VERSION 5.7 ;
  NOWIREEXTENSIONATPIN ON ;
  DIVIDERCHAR "/" ;
  BUSBITCHARS "[]" ;
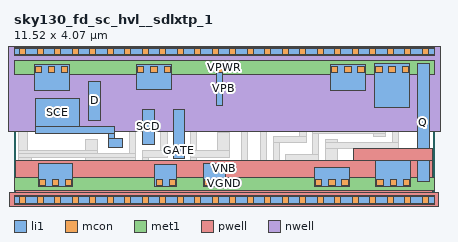
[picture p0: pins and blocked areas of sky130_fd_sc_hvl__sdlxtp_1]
MACRO sky130_fd_sc_hvl__sdlxtp_1
  CLASS BLOCK ;
  FOREIGN sky130_fd_sc_hvl__sdlxtp_1 ;
  ORIGIN 0.000 0.000 ;
  SIZE 11.520 BY 4.070 ;
  PIN D
    ANTENNAGATEAREA 0.585000 ;
    PORT
      LAYER li1 ;
        RECT 2.040 2.185 2.370 3.260 ;
    END
  END D
  PIN GATE
    ANTENNAGATEAREA 0.585000 ;
    PORT
      LAYER li1 ;
        RECT 4.370 1.145 4.665 2.495 ;
    END
  END GATE
  PIN SCD
    ANTENNAGATEAREA 0.585000 ;
    PORT
      LAYER li1 ;
        RECT 3.515 1.525 3.860 2.495 ;
    END
  END SCD
  PIN SCE
    ANTENNAGATEAREA 1.005000 ;
    PORT
      LAYER li1 ;
        RECT 0.585 2.005 1.795 2.775 ;
        RECT 0.585 1.835 2.770 2.005 ;
        RECT 2.600 1.695 2.770 1.835 ;
        RECT 2.600 1.445 2.985 1.695 ;
    END
  END SCE
  PIN VGND
    USE GROUND ;
    PORT
      LAYER li1 ;
        RECT 0.660 0.365 1.610 0.995 ;
        RECT 3.865 0.365 4.455 0.975 ;
        RECT 5.205 0.365 5.795 0.995 ;
        RECT 8.245 0.365 9.195 0.895 ;
        RECT 9.925 0.365 10.875 1.225 ;
      LAYER mcon ;
        RECT 0.690 0.395 0.860 0.565 ;
        RECT 1.050 0.395 1.220 0.565 ;
        RECT 1.410 0.395 1.580 0.565 ;
        RECT 3.895 0.395 4.065 0.565 ;
        RECT 4.255 0.395 4.425 0.565 ;
        RECT 5.235 0.395 5.405 0.565 ;
        RECT 5.595 0.395 5.765 0.565 ;
        RECT 8.275 0.395 8.445 0.565 ;
        RECT 8.635 0.395 8.805 0.565 ;
        RECT 8.995 0.395 9.165 0.565 ;
        RECT 9.955 0.395 10.125 0.565 ;
        RECT 10.315 0.395 10.485 0.565 ;
        RECT 10.675 0.395 10.845 0.565 ;
      LAYER met1 ;
        RECT 0.000 0.255 11.520 0.625 ;
    END
  END VGND
  PIN VNB
    ANTENNADIFFAREA 1.958400 ;
    PORT
      LAYER pwell ;
        RECT 9.325 1.085 11.490 1.415 ;
        RECT 0.040 0.215 11.490 1.085 ;
        RECT -0.130 -0.215 11.650 0.215 ;
      LAYER li1 ;
        RECT 0.000 -0.085 11.520 0.085 ;
      LAYER mcon ;
        RECT 0.155 -0.085 0.325 0.085 ;
        RECT 0.635 -0.085 0.805 0.085 ;
        RECT 1.115 -0.085 1.285 0.085 ;
        RECT 1.595 -0.085 1.765 0.085 ;
        RECT 2.075 -0.085 2.245 0.085 ;
        RECT 2.555 -0.085 2.725 0.085 ;
        RECT 3.035 -0.085 3.205 0.085 ;
        RECT 3.515 -0.085 3.685 0.085 ;
        RECT 3.995 -0.085 4.165 0.085 ;
        RECT 4.475 -0.085 4.645 0.085 ;
        RECT 4.955 -0.085 5.125 0.085 ;
        RECT 5.435 -0.085 5.605 0.085 ;
        RECT 5.915 -0.085 6.085 0.085 ;
        RECT 6.395 -0.085 6.565 0.085 ;
        RECT 6.875 -0.085 7.045 0.085 ;
        RECT 7.355 -0.085 7.525 0.085 ;
        RECT 7.835 -0.085 8.005 0.085 ;
        RECT 8.315 -0.085 8.485 0.085 ;
        RECT 8.795 -0.085 8.965 0.085 ;
        RECT 9.275 -0.085 9.445 0.085 ;
        RECT 9.755 -0.085 9.925 0.085 ;
        RECT 10.235 -0.085 10.405 0.085 ;
        RECT 10.715 -0.085 10.885 0.085 ;
        RECT 11.195 -0.085 11.365 0.085 ;
      LAYER met1 ;
        RECT 0.000 -0.115 11.520 0.115 ;
    END
  END VNB
  PIN VPB
    ANTENNADIFFAREA 1.958400 ;
    PORT
      LAYER nwell ;
        RECT -0.330 1.885 11.850 4.485 ;
      LAYER li1 ;
        RECT 0.000 3.985 11.520 4.155 ;
      LAYER mcon ;
        RECT 0.155 3.985 0.325 4.155 ;
        RECT 0.635 3.985 0.805 4.155 ;
        RECT 1.115 3.985 1.285 4.155 ;
        RECT 1.595 3.985 1.765 4.155 ;
        RECT 2.075 3.985 2.245 4.155 ;
        RECT 2.555 3.985 2.725 4.155 ;
        RECT 3.035 3.985 3.205 4.155 ;
        RECT 3.515 3.985 3.685 4.155 ;
        RECT 3.995 3.985 4.165 4.155 ;
        RECT 4.475 3.985 4.645 4.155 ;
        RECT 4.955 3.985 5.125 4.155 ;
        RECT 5.435 3.985 5.605 4.155 ;
        RECT 5.915 3.985 6.085 4.155 ;
        RECT 6.395 3.985 6.565 4.155 ;
        RECT 6.875 3.985 7.045 4.155 ;
        RECT 7.355 3.985 7.525 4.155 ;
        RECT 7.835 3.985 8.005 4.155 ;
        RECT 8.315 3.985 8.485 4.155 ;
        RECT 8.795 3.985 8.965 4.155 ;
        RECT 9.275 3.985 9.445 4.155 ;
        RECT 9.755 3.985 9.925 4.155 ;
        RECT 10.235 3.985 10.405 4.155 ;
        RECT 10.715 3.985 10.885 4.155 ;
        RECT 11.195 3.985 11.365 4.155 ;
      LAYER met1 ;
        RECT 0.000 3.955 11.520 4.185 ;
    END
  END VPB
  PIN VPWR
    USE POWER ;
    PORT
      LAYER li1 ;
        RECT 0.560 2.995 1.510 3.705 ;
        RECT 3.365 3.025 4.315 3.725 ;
        RECT 5.545 2.585 5.715 3.705 ;
        RECT 8.685 3.005 9.635 3.705 ;
        RECT 9.895 2.535 10.845 3.755 ;
      LAYER mcon ;
        RECT 0.590 3.505 0.760 3.675 ;
        RECT 0.950 3.505 1.120 3.675 ;
        RECT 1.310 3.505 1.480 3.675 ;
        RECT 3.395 3.505 3.565 3.675 ;
        RECT 3.755 3.505 3.925 3.675 ;
        RECT 4.115 3.505 4.285 3.675 ;
        RECT 5.545 3.505 5.715 3.675 ;
        RECT 8.715 3.505 8.885 3.675 ;
        RECT 9.075 3.505 9.245 3.675 ;
        RECT 9.435 3.505 9.605 3.675 ;
        RECT 9.925 3.505 10.095 3.675 ;
        RECT 10.285 3.505 10.455 3.675 ;
        RECT 10.645 3.505 10.815 3.675 ;
      LAYER met1 ;
        RECT 0.000 3.445 11.520 3.815 ;
    END
  END VPWR
  PIN Q
    ANTENNADIFFAREA 0.626250 ;
    PORT
      LAYER li1 ;
        RECT 11.060 0.515 11.400 3.755 ;
    END
  END Q
  OBS
      LAYER li1 ;
        RECT 0.130 1.345 0.380 3.395 ;
        RECT 2.575 2.845 2.825 3.725 ;
        RECT 4.495 3.635 5.365 3.805 ;
        RECT 4.495 2.845 4.665 3.635 ;
        RECT 2.575 2.675 4.665 2.845 ;
        RECT 2.950 1.905 3.335 2.495 ;
        RECT 1.965 1.345 2.295 1.655 ;
        RECT 0.130 1.265 2.295 1.345 ;
        RECT 3.165 1.265 3.335 1.905 ;
        RECT 4.030 1.345 4.200 2.675 ;
        RECT 0.130 1.175 3.335 1.265 ;
        RECT 0.130 0.495 0.480 1.175 ;
        RECT 1.965 1.095 3.335 1.175 ;
        RECT 3.515 1.175 4.200 1.345 ;
        RECT 4.845 1.345 5.015 3.455 ;
        RECT 5.195 2.405 5.365 3.635 ;
        RECT 5.895 3.595 7.250 3.765 ;
        RECT 5.895 2.405 6.065 3.595 ;
        RECT 5.195 2.235 6.065 2.405 ;
        RECT 6.245 2.585 6.575 3.415 ;
        RECT 6.755 2.925 7.250 3.595 ;
        RECT 7.700 2.925 8.030 3.755 ;
        RECT 5.590 1.345 5.920 1.845 ;
        RECT 4.845 1.175 5.920 1.345 ;
        RECT 3.515 0.915 3.685 1.175 ;
        RECT 4.845 0.975 5.015 1.175 ;
        RECT 6.245 0.975 6.415 2.585 ;
        RECT 6.755 0.975 6.925 2.925 ;
        RECT 7.860 2.825 8.030 2.925 ;
        RECT 7.860 2.655 8.920 2.825 ;
        RECT 7.840 2.215 8.570 2.475 ;
        RECT 7.840 1.755 8.010 2.215 ;
        RECT 8.750 2.005 8.920 2.655 ;
        RECT 9.385 2.355 9.715 2.675 ;
        RECT 9.385 2.185 10.550 2.355 ;
        RECT 2.420 0.745 3.685 0.915 ;
        RECT 2.420 0.495 2.750 0.745 ;
        RECT 4.695 0.515 5.025 0.975 ;
        RECT 6.045 0.435 6.415 0.975 ;
        RECT 6.595 0.615 6.925 0.975 ;
        RECT 7.105 1.585 8.010 1.755 ;
        RECT 8.190 1.835 10.200 2.005 ;
        RECT 7.105 0.435 7.275 1.585 ;
        RECT 8.190 1.245 8.360 1.835 ;
        RECT 9.870 1.755 10.200 1.835 ;
        RECT 7.455 1.075 8.360 1.245 ;
        RECT 8.540 1.575 8.870 1.655 ;
        RECT 10.380 1.575 10.550 2.185 ;
        RECT 8.540 1.405 10.550 1.575 ;
        RECT 8.540 1.075 8.870 1.405 ;
        RECT 7.455 0.495 7.705 1.075 ;
        RECT 9.415 0.845 9.745 1.405 ;
        RECT 6.045 0.265 7.275 0.435 ;
  END
END sky130_fd_sc_hvl__sdlxtp_1
END LIBRARY

